VERSION 5.7 ;
  NOWIREEXTENSIONATPIN ON ;
  DIVIDERCHAR "/" ;
  BUSBITCHARS "[]" ;
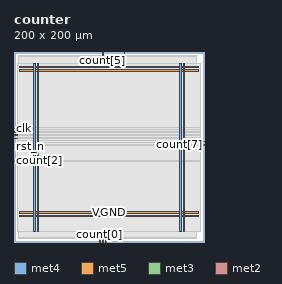
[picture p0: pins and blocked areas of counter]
MACRO counter
  CLASS BLOCK ;
  FOREIGN counter ;
  ORIGIN 0.000 0.000 ;
  SIZE 200.000 BY 200.000 ;
  PIN VGND
    DIRECTION INOUT ;
    USE GROUND ;
    PORT
      LAYER met4 ;
        RECT 24.340 10.640 25.940 187.920 ;
    END
    PORT
      LAYER met4 ;
        RECT 177.940 10.640 179.540 187.920 ;
    END
    PORT
      LAYER met5 ;
        RECT 5.280 30.030 194.360 31.630 ;
    END
    PORT
      LAYER met5 ;
        RECT 5.280 183.210 194.360 184.810 ;
    END
  END VGND
  PIN VPWR
    DIRECTION INOUT ;
    USE POWER ;
    PORT
      LAYER met4 ;
        RECT 21.040 10.640 22.640 187.920 ;
    END
    PORT
      LAYER met4 ;
        RECT 174.640 10.640 176.240 187.920 ;
    END
    PORT
      LAYER met5 ;
        RECT 5.280 26.730 194.360 28.330 ;
    END
    PORT
      LAYER met5 ;
        RECT 5.280 179.910 194.360 181.510 ;
    END
  END VPWR
  PIN clk
    DIRECTION INPUT ;
    USE SIGNAL ;
    ANTENNAGATEAREA 0.852000 ;
    PORT
      LAYER met3 ;
        RECT 0.000 119.040 4.000 119.640 ;
    END
  END clk
  PIN count[0]
    DIRECTION OUTPUT ;
    USE SIGNAL ;
    ANTENNADIFFAREA 0.445500 ;
    PORT
      LAYER met2 ;
        RECT 90.250 0.000 90.530 4.000 ;
    END
  END count[0]
  PIN count[1]
    DIRECTION OUTPUT ;
    USE SIGNAL ;
    ANTENNADIFFAREA 0.445500 ;
    PORT
      LAYER met2 ;
        RECT 93.470 0.000 93.750 4.000 ;
    END
  END count[1]
  PIN count[2]
    DIRECTION OUTPUT ;
    USE SIGNAL ;
    ANTENNADIFFAREA 0.445500 ;
    PORT
      LAYER met3 ;
        RECT 0.000 85.040 4.000 85.640 ;
    END
  END count[2]
  PIN count[3]
    DIRECTION OUTPUT ;
    USE SIGNAL ;
    ANTENNADIFFAREA 0.445500 ;
    PORT
      LAYER met3 ;
        RECT 0.000 112.240 4.000 112.840 ;
    END
  END count[3]
  PIN count[4]
    DIRECTION OUTPUT ;
    USE SIGNAL ;
    ANTENNADIFFAREA 0.445500 ;
    PORT
      LAYER met3 ;
        RECT 0.000 115.640 4.000 116.240 ;
    END
  END count[4]
  PIN count[5]
    DIRECTION OUTPUT ;
    USE SIGNAL ;
    ANTENNADIFFAREA 0.445500 ;
    PORT
      LAYER met2 ;
        RECT 93.470 196.000 93.750 200.000 ;
    END
  END count[5]
  PIN count[6]
    DIRECTION OUTPUT ;
    USE SIGNAL ;
    ANTENNADIFFAREA 0.445500 ;
    PORT
      LAYER met2 ;
        RECT 116.010 196.000 116.290 200.000 ;
    END
  END count[6]
  PIN count[7]
    DIRECTION OUTPUT ;
    USE SIGNAL ;
    ANTENNADIFFAREA 0.445500 ;
    PORT
      LAYER met3 ;
        RECT 196.000 102.040 200.000 102.640 ;
    END
  END count[7]
  PIN enable
    DIRECTION INPUT ;
    USE SIGNAL ;
    ANTENNAGATEAREA 0.213000 ;
    PORT
      LAYER met2 ;
        RECT 96.690 0.000 96.970 4.000 ;
    END
  END enable
  PIN overflow
    DIRECTION OUTPUT ;
    USE SIGNAL ;
    ANTENNADIFFAREA 0.445500 ;
    PORT
      LAYER met3 ;
        RECT 196.000 105.440 200.000 106.040 ;
    END
  END overflow
  PIN rst_n
    DIRECTION INPUT ;
    USE SIGNAL ;
    ANTENNAGATEAREA 0.213000 ;
    PORT
      LAYER met3 ;
        RECT 0.000 108.840 4.000 109.440 ;
    END
  END rst_n
  OBS
      LAYER nwell ;
        RECT 5.330 10.795 194.310 187.870 ;
      LAYER li1 ;
        RECT 5.520 10.795 194.120 187.765 ;
      LAYER met1 ;
        RECT 4.210 10.640 194.120 187.920 ;
      LAYER met2 ;
        RECT 4.230 195.720 93.190 196.000 ;
        RECT 94.030 195.720 115.730 196.000 ;
        RECT 116.570 195.720 192.190 196.000 ;
        RECT 4.230 4.280 192.190 195.720 ;
        RECT 4.230 4.000 89.970 4.280 ;
        RECT 90.810 4.000 93.190 4.280 ;
        RECT 94.030 4.000 96.410 4.280 ;
        RECT 97.250 4.000 192.190 4.280 ;
      LAYER met3 ;
        RECT 3.990 120.040 196.000 187.845 ;
        RECT 4.400 118.640 196.000 120.040 ;
        RECT 3.990 116.640 196.000 118.640 ;
        RECT 4.400 115.240 196.000 116.640 ;
        RECT 3.990 113.240 196.000 115.240 ;
        RECT 4.400 111.840 196.000 113.240 ;
        RECT 3.990 109.840 196.000 111.840 ;
        RECT 4.400 108.440 196.000 109.840 ;
        RECT 3.990 106.440 196.000 108.440 ;
        RECT 3.990 105.040 195.600 106.440 ;
        RECT 3.990 103.040 196.000 105.040 ;
        RECT 3.990 101.640 195.600 103.040 ;
        RECT 3.990 86.040 196.000 101.640 ;
        RECT 4.400 84.640 196.000 86.040 ;
        RECT 3.990 10.715 196.000 84.640 ;
  END
END counter
END LIBRARY

